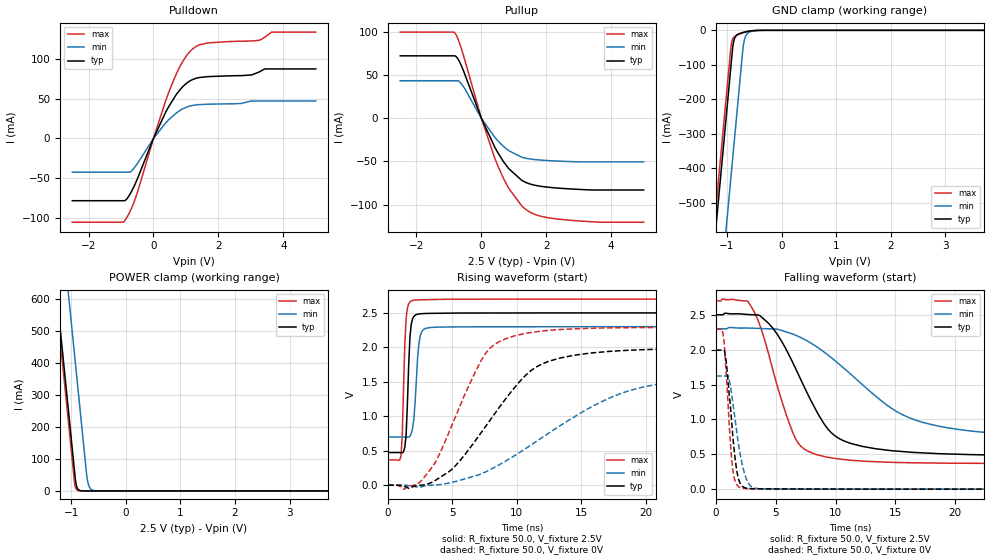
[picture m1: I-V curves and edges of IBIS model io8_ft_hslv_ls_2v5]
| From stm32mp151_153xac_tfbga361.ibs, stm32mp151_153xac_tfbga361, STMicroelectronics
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[Model]   io8_ft_hslv_ls_2v5
Model_type I/O
Polarity   Non-Inverting
Enable   Active-Low
| CAP_THRESHOLD on pad IOFT is "UDTCAPC" :
| Rising=20.00f vddiom   Falling=80.00f vddiom
| C_comp min and max val. don't necessarily correlate with the min and max pvt
| but are the smallest and greatest pad capacitance found.
| var   typ   min   max
C_comp   3.57714pF  3.54080pF  3.63503pF
|C_comp_pullup   2.11645pF  2.17895pF  2.03325pF
|C_comp_pulldown   1.46069pF  1.36185pF  1.60178pF
Vinl = 920.0mV
Vinh = 1.62V
Vmeas = 1.25V   | Reference voltage for timing measurements
Cref  = 50.0pF   | Timing specification test load capacitance value
Rref  = 100.0MOhm   | Timing specification test load resistance value
Vref  = 0V   | Timing specification test load voltage
[Model Spec]
| TIME_THRESHOLD on pin ZIV11 is "CMOS" :
| Rising=40.00f vdd   Falling=60.00f vdd
Vinl 1.03860V 964.60000mV 1.11860V
Vinh 1.36340V 1.26240V 1.44140V
| variable   typ   min   max
[Temperature Range] 25.0 140.0 -40.0
| variable   typ   min   max
[Voltage Range] 2.5V 2.3V 2.7V
| variable   typ   min   max
[POWER Clamp Reference] 2.5V 2.3V 2.7V
| variable   typ   min   max
[GND Clamp Reference] 0V 0V 0V
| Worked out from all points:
|   slope of the pulldown table from 0 to 0.375 V, typ, clamps not added: 11.3 ohm
|   slope of the pullup table from 0 to 0.375 V, typ, clamps not added: 12.3 ohm
|   GND clamp passes 1 mA (typ) near -0.52 V on its own axis
|   POWER clamp passes 1 mA (typ) near -0.83 V on its own axis
|   rising waveform, R_fixture 50.0, V_fixture 2.5V: 20-80 % time 252ps typ, 332ps min, 234ps max; typ from 0.473 V to 2.5 V
|   falling waveform, R_fixture 50.0, V_fixture 2.5V: 20-80 % time 3.71ns typ, 7.3ns min, 2.47ns max; typ from 2.5 V to 0.473 V
|   rising waveform, R_fixture 50.0, V_fixture 0V: 20-80 % time 4.92ns typ, 8.72ns min, 3.3ns max; typ from 0 V to 1.99 V
|   falling waveform, R_fixture 50.0, V_fixture 0V: 20-80 % time 643ps typ, 879ps min, 507ps max; typ from 1.99 V to 0 V
[POWER Clamp]
-2.5V     2.719A     3.084A     2.683A
-1.28V    644.8mA    1.01A      609.5mA
-1.26V    610.8mA    976.1mA    575.5mA
-1.04V    236.8mA    602.1mA    201.5mA
-940mV    66.83mA    432.1mA    31.5mA
-930mV    49.83mA    415.1mA    19.15mA
-910mV    22.88mA    381.1mA    7.077mA
-880mV    7.117mA    330.1mA    1.59mA
-710mV    9.523uA    43.89mA    337nA
-670mV    2.008uA    14.27mA    46.3nA
-600mV    132.9nA    1.998mA    1.599nA
5V        0A         0A         0A
[GND Clamp]
-2.5V     -2.779A    -3.101A    -2.723A
-1.26V    -670.8mA   -992.7mA   -614.5mA
-930mV    -109.8mA   -431.7mA   -53.54mA
-910mV    -75.83mA   -397.7mA   -32.67mA
-880mV    -35.28mA   -346.7mA   -21.39mA
-850mV    -20.07mA   -295.7mA   -16.99mA
-790mV    -10.9mA    -193.7mA   -12.02mA
-710mV    -6.374mA   -57.93mA   -7.219mA
-690mV    -5.545mA   -35.45mA   -6.225mA
-640mV    -3.775mA   -11.96mA   -4.068mA
-540mV    -1.354mA   -2.661mA   -1.223mA
5V        6.965nA    2.133uA    347.4pA
| variable   typ   min   max
[Pullup Reference] 2.5V 2.3V 2.7V
| variable   typ   min   max
[Pulldown Reference] 0V 0V 0V
[Pullup]
-2.5V     72.33mA    43.48mA    99.82mA
-800mV    72.04mA    43.48mA    97.99mA
-700mV    67.32mA    43.03mA    89.87mA
-570mV    56.71mA    37.64mA    75.05mA
0V        9.19pA     1.4nA      5.79pA
410mV     -33.26mA   -21.8mA    -45.97mA
840mV     -58.17mA   -37.44mA   -80.95mA
1.36V     -74.11mA   -46.17mA   -105.2mA
1.71V     -78mA      -48.02mA   -112.1mA
2.4V      -80.94mA   -49.62mA   -116.8mA
3.63V     -83.02mA   -50.48mA   -120.3mA
5V        -83.02mA   -50.48mA   -120.3mA
[Pulldown]
-2.5V     -78.63mA   -42.6mA    -105.8mA
-870mV    -78.28mA   -42.6mA    -102.9mA
-710mV    -69.32mA   -42.37mA   -91.24mA
-540mV    -55.23mA   -34.22mA   -73.64mA
0V        0A         -2pA       0A
470mV     40.29mA    23.69mA    58.27mA
850mV     63.07mA    36.18mA    93.59mA
1.21V     74.52mA    41.78mA    113.2mA
1.67V     78.14mA    43.3mA     120.7mA
3.22V     83.36mA    47.41mA    123.9mA
3.64V     87.89mA    47.41mA    134.4mA
5V        87.89mA    47.41mA    134.4mA
[Ramp]
dV/dt_r 1.19545V/4.91677ns 973.4037mV/8.72114ns 1.37489V/3.29665ns
dV/dt_f 1.21605V/3.70901ns 960.46445mV/7.30278ns 1.39953V/2.47124ns
R_load = 50.0
| Removed startup time: 0s 0s 0s  .
| Removed end time: 37.9ns.
[Rising Waveform]
R_fixture   = 50.0
V_fixture   = 2.5V
V_fixture_min = 2.3V
V_fixture_max = 2.7V
0s        473.2mV    699.2mV    367.5mV
1ns       471.2mV    699.3mV    422.8mV
1.1ns     468.9mV    699.3mV    706.3mV
1.3ns     550mV      699mV      2.037V
1.4ns     722.3mV    698.1mV    2.415V
1.7ns     2.151V     709.6mV    2.658V
1.9ns     2.412V     822.8mV    2.679V
2.4ns     2.484V     2.062V     2.689V
3ns       2.492V     2.279V     2.691V
37.9ns    2.5V       2.3V       2.7V
| Removed startup time: 0s 0s 0s  .
| Removed end time: 299.9ns.
[Falling Waveform]
R_fixture   = 50.0
V_fixture   = 2.5V
V_fixture_min = 2.3V
V_fixture_max = 2.7V
0s        2.5V       2.3V       2.7V
3ns       2.5V       2.308V     2.602V
4.8ns     2.298V     2.299V     1.68V
7ns       1.604V     2.183V     633.8mV
9.5ns     834.9mV    1.905V     452.8mV
12.5ns    605.2mV    1.46V      399.2mV
15.5ns    539.8mV    1.077V     380.9mV
19.2ns    505.7mV    884.9mV    372.7mV
37.4ns    474.8mV    719.7mV    367.5mV
299.9ns   473.2mV    699.2mV    367.4mV
| Removed startup time: 0s 0s 0s  .
| Removed end time: 299.9ns.
[Rising Waveform]
R_fixture   = 50.0
V_fixture   = 0V
V_fixture_min = 0V
V_fixture_max = 0V
0s        121.5nV    120.2nV    -3.624uV
2.1ns     -10.51mV   -20.62mV   5.073mV
3.4ns     41.57mV    46.01uV    255.4mV
7ns       702.1mV    147.2mV    1.724V
8.2ns     1.017V     250.7mV    2.031V
11.3ns    1.689V     607.8mV    2.22V
15.1ns    1.902V     1.063V     2.273V
21.6ns    1.975V     1.483V     2.289V
37.4ns    1.992V     1.612V     2.291V
299.9ns   1.992V     1.622V     2.291V
| Removed startup time: 0s 0s 0s  .
| Removed end time: 37.9ns.
[Falling Waveform]
R_fixture   = 50.0
V_fixture   = 0V
V_fixture_min = 0V
V_fixture_max = 0V
0s        1.992V     1.622V     2.291V
500ps     1.992V     1.622V     2.297V
800ps     1.906V     1.622V     1.798V
1.1ns     1.367V     1.581V     947.2mV
1.4ns     775.4mV    1.245V     283mV
1.7ns     307.8mV    864.7mV    75.37mV
2.1ns     60.82mV    432.1mV    17.99mV
2.7ns     9.659mV    88.46mV    7.38mV
3.6ns     4.647mV    6.815mV    5.727mV
37.9ns    6.876uV    62.89uV    15.16uV
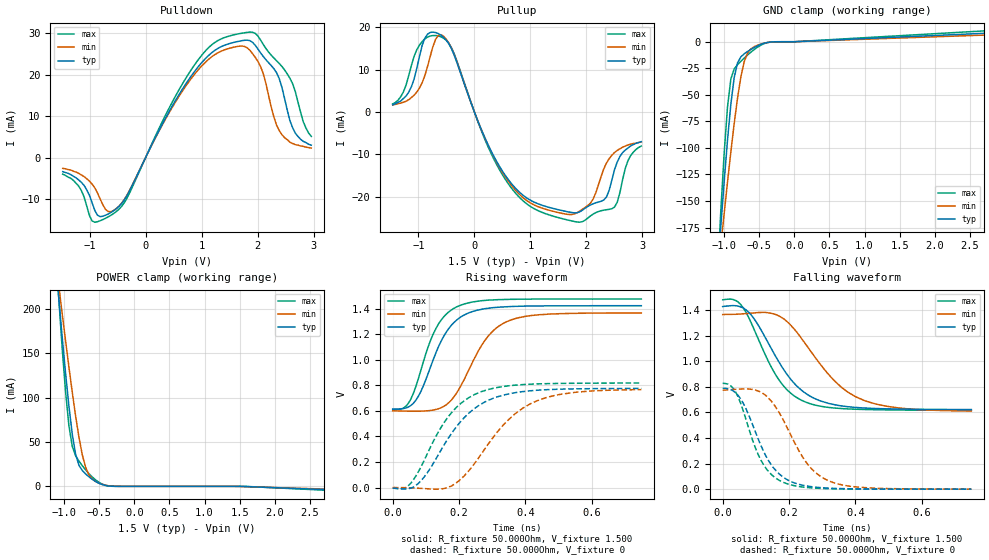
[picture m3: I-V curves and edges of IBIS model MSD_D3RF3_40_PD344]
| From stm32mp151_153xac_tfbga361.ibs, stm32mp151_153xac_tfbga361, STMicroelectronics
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[Model] MSD_D3RF3_40_PD344
Model_type   I/O
C_comp 2.325pF   2.244pF   2.446pF
Vinh = 925.000mV
Vinl = 575.000mV
Vmeas = 750.000mV
Vref = 750.000mV
[Model Spec]
Vinh   925.000mV   888.000mV   963.000mV
Vinl   575.000mV   538.000mV   613.000mV
Vmeas   750.000mV   713.000mV   788.000mV
Vref   750.000mV   713.000mV   788.000mV
[Temperature Range]   25.000   125.000   -40.000
[Voltage Range]   1.500V   1.425V   1.575V
[GND Clamp Reference]   0.00V   0.00V   0.00V
[Pulldown Reference]   0.00V   0.00V   0.00V
[POWER Clamp Reference]   1.500V   1.425V   1.575V
[Pullup Reference]   1.500V   1.425V   1.575V
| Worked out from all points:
|   slope of the pulldown table from 0 to 0.225 V, typ, clamps not added: 36.6 ohm
|   slope of the pullup table from 0 to 0.225 V, typ, clamps not added: 31.2 ohm
|   GND clamp passes 1 mA (typ) near -0.40 V on its own axis
|   POWER clamp passes 1 mA (typ) near -0.41 V on its own axis
|   rising waveform, R_fixture 50.000Ohm, V_fixture 1.500: 20-80 % time 85.1ps typ, 102ps min, 74.9ps max; typ from 0.614 V to 1.42 V
|   rising waveform, R_fixture 50.000Ohm, V_fixture 0: 20-80 % time 134ps typ, 151ps min, 118ps max; typ from -0.004 V to 0.776 V
|   falling waveform, R_fixture 50.000Ohm, V_fixture 1.500: 20-80 % time 122ps typ, 148ps min, 105ps max; typ from 1.43 V to 0.622 V
|   falling waveform, R_fixture 50.000Ohm, V_fixture 0: 20-80 % time 86.4ps typ, 104ps min, 74.4ps max; typ from 0.789 V to 0 V
[GND Clamp]
-1.48V    -593.9mA   -479.7mA   -763.2mA
-1.098V   -218.2mA   -223.4mA   -220.2mA
-1.05V    -174.1mA   -192.4mA   -159.6mA
-1.002V   -131.9mA   -161.9mA   -105.2mA
-954.6mV  -92.83mA   -132.3mA   -61.52mA
-906.8mV  -59.01mA   -103.9mA   -35.14mA
-859.1mV  -33.8mA    -77.16mA   -25.62mA
-811.4mV  -19.9mA    -53.08mA   -21.6mA
-715.9mV  -11.4mA    -18.73mA   -15.4mA
-572.7mV  -5.412mA   -4.636mA   -7.313mA
-334.1mV  -240.8uA   -308.8uA   -242.5uA
2.959V    8.682mA    6.832mA    11.15mA
[Power Clamp]
-1.459V   577.4mA    478.9mA    722.8mA
-1.077V   210.9mA    225.3mA    210.2mA
-1.03V    168.1mA    194.5mA    155.5mA
-981.8mV  127.5mA    164.2mA    106.7mA
-934.1mV  90.43mA    134.6mA    68.21mA
-886.4mV  58.96mA    106.1mA    45.13mA
-838.6mV  36.12mA    79.33mA    34.57mA
-743.2mV  17.82mA    35.48mA    23.27mA
-647.7mV  10.71mA    12.79mA    14.31mA
-552.3mV  5.453mA    5.392mA    7.2mA
-313.6mV  90.62uA    219.4uA    108.4uA
2.98V     -4.416mA   -3.704mA   -5.362mA
[Pulldown]
-1.48V    -3.4mA     -2.6mA     -4mA
-1.193V   -5.4mA     -3.8mA     -6.9mA
-954.6mV  -10.92mA   -6.4mA     -15.27mA
-811.4mV  -14.22mA   -9.94mA    -15.22mA
-525mV    -12.36mA   -12.3mA    -13.02mA
906.8mV   21.31mA    20.61mA    22.96mA
1.289V    26.28mA    25.22mA    28.17mA
1.766V    28.25mA    26.78mA    30.06mA
2.052V    25.24mA    21.96mA    28.33mA
2.434V    16.92mA    5.5mA      21.96mA
2.673V    5.9mA      3.1mA      15.9mA
2.959V    3mA        2.3mA      5.1mA
[Pullup]
-1.459V   1.7mA      1.657mA    1.929mA
-1.173V   4.7mA      2.929mA    8.628mA
-838.6mV  18.38mA    10.7mA     17.71mA
-695.5mV  18.8mA     17.13mA    18.09mA
-552.3mV  17.7mA     17.94mA    17.47mA
640.9mV   -16.58mA   -16.97mA   -17.61mA
1.834V    -23.79mA   -23.77mA   -25.99mA
2.12V     -21.67mA   -20.55mA   -24.11mA
2.311V    -20.78mA   -13.39mA   -23.18mA
2.502V    -13.6mA    -9.557mA   -22.45mA
2.741V    -8.5mA     -7.786mA   -11.5mA
2.98V     -7mA       -7.043mA   -8.029mA
[Ramp]
R_load=50.000Ohm
dV/dt_r   473.460mV/109.500ps  459.269mV/127.500ps  503.190mV/97.000ps
dV/dt_f   473.460mV/104.500ps  459.269mV/128.000ps  503.190mV/90.000ps
[Rising waveform]
R_fixture=50.000Ohm
V_fixture=1.500
V_fixture_min=1.425
V_fixture_max=1.575
0s        614.5mV    600.9mV    611.3mV
39ps      622.5mV    598.7mV    634.6mV
69ps      680.8mV    597.9mV    785.5mV
108ps     901.6mV    602mV      1.11V
131ps     1.06V      612mV      1.248V
192ps     1.309V     737.8mV    1.413V
276ps     1.399V     1.145V     1.464V
345ps     1.415V     1.3V       1.472V
467ps     1.422V     1.357V     1.475V
749ps     1.423V     1.366V     1.475V
[Rising waveform]
R_fixture=50.000Ohm
V_fixture=0
0s        -3.738mV   807.5uV    -3.72mV
39ps      -10.46mV   -683uV     194.6uV
77ps      32.35mV    -4.576mV   122.6mV
169ps     392.7mV    4.086mV    559.9mV
207ps     523.1mV    70.71mV    662.6mV
253ps     631mV      211.8mV    735.6mV
345ps     730.7mV    521.5mV    795.1mV
437ps     762.2mV    681.6mV    811.3mV
552ps     772.7mV    746.3mV    816.4mV
749ps     776mV      766.7mV    818.4mV
[Falling waveform]
R_fixture=50.000Ohm
V_fixture=1.500
V_fixture_min=1.425
V_fixture_max=1.575
0s        1.427V     1.365V     1.48V
46ps      1.431V     1.368V     1.464V
77ps      1.386V     1.374V     1.349V
138ps     1.139V     1.378V     996.9mV
169ps     996mV      1.354V     855.9mV
245ps     758.2mV    1.151V     686mV
337ps     660.4mV    846.2mV    634.2mV
429ps     634.1mV    690.3mV    622.7mV
552ps     625.5mV    629.3mV    618.2mV
749ps     622.2mV    610.6mV    617.1mV
[Falling waveform]
R_fixture=50.000Ohm
V_fixture=0
0s        788.6mV    774mV      827mV
39ps      753.4mV    780.5mV    759.5mV
69ps      634.8mV    783.6mV    554.3mV
115ps     341.9mV    757.9mV    227.4mV
146ps     191.2mV    689.6mV    116.1mV
184ps     90.9mV     534.2mV    51.97mV
253ps     24.96mV    205mV      13.15mV
322ps     7.88mV     61.99mV    3.518mV
444ps     1.173mV    9.74mV     459.8uV
749ps     25.69uV    248.7uV    20.75uV
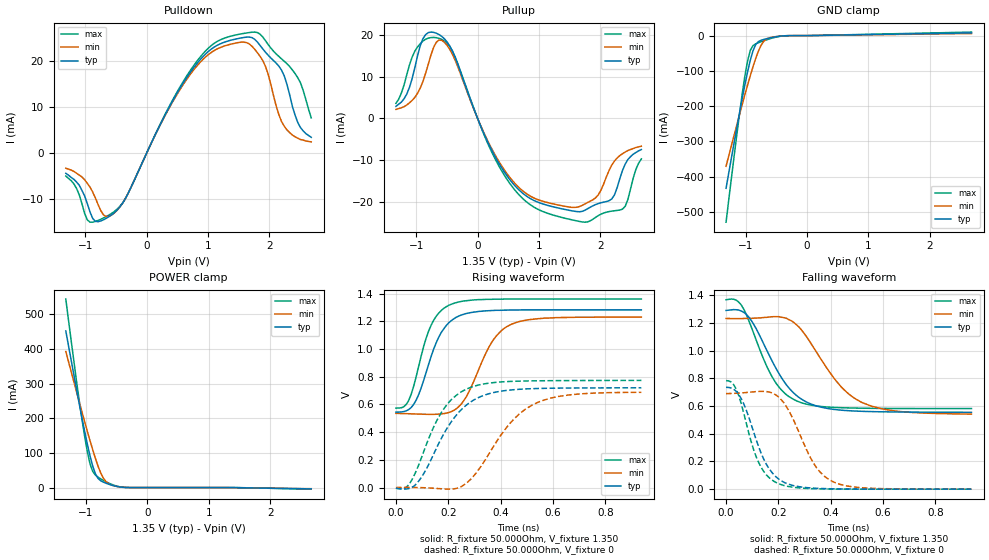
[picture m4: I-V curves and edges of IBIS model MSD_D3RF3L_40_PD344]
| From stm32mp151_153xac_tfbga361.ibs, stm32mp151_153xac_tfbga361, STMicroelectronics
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[Model] MSD_D3RF3L_40_PD344
Model_type   I/O
C_comp 2.333pF   2.249pF   2.455pF
Vinh = 810.000mV
Vinl = 540.000mV
Vmeas = 675.000mV
Vref = 675.000mV
[Model Spec]
Vinh   810.000mV   777.000mV   860.000mV
Vinl   540.000mV   507.000mV   590.000mV
Vmeas   675.000mV   642.000mV   725.000mV
Vref   675.000mV   642.000mV   725.000mV
[Temperature Range]   25.000   125.000   -40.000
[Voltage Range]   1.350V   1.283V   1.450V
[GND Clamp Reference]   0.00V   0.00V   0.00V
[Pulldown Reference]   0.00V   0.00V   0.00V
[POWER Clamp Reference]   1.350V   1.283V   1.450V
[Pullup Reference]   1.350V   1.283V   1.450V
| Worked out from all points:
|   slope of the pulldown table from 0 to 0.203 V, typ, clamps not added: 35.7 ohm
|   slope of the pullup table from 0 to 0.203 V, typ, clamps not added: 29.7 ohm
|   GND clamp passes 1 mA (typ) near -0.41 V on its own axis
|   POWER clamp passes 1 mA (typ) near -0.41 V on its own axis
|   rising waveform, R_fixture 50.000Ohm, V_fixture 1.350: 20-80 % time 87.9ps typ, 108ps min, 75.3ps max; typ from 0.545 V to 1.28 V
|   rising waveform, R_fixture 50.000Ohm, V_fixture 0: 20-80 % time 139ps typ, 165ps min, 119ps max; typ from -0.005 V to 0.72 V
|   falling waveform, R_fixture 50.000Ohm, V_fixture 1.350: 20-80 % time 135ps typ, 164ps min, 113ps max; typ from 1.29 V to 0.554 V
|   falling waveform, R_fixture 50.000Ohm, V_fixture 0: 20-80 % time 91.3ps typ, 109ps min, 78ps max; typ from 0.735 V to 0 V
[GND Clamp]
-1.318V   -432.8mA   -370.3mA   -528.8mA
-1.142V   -260.6mA   -252.7mA   -280.2mA
-1.055V   -178.2mA   -195.3mA   -165.2mA
-1.011V   -139.1mA   -167.2mA   -114.1mA
-966.7mV  -102.3mA   -139.7mA   -71.26mA
-922.7mV  -69.52mA   -113.2mA   -41.65mA
-878.8mV  -42.92mA   -87.94mA   -28.29mA
-834.9mV  -25.34mA   -64.54mA   -23.37mA
-790.9mV  -16.86mA   -43.9mA    -20.2mA
-703mV    -10.78mA   -15.99mA   -14.6mA
-527.3mV  -3.885mA   -3.295mA   -5.182mA
2.68V     7.735mA    6.026mA    10.03mA
[Power Clamp]
-1.33V    451.9mA    392.5mA    543.7mA
-1.111V   241.7mA    247mA      250.6mA
-1.023V   162.1mA    190.1mA    147.8mA
-978.8mV  125mA      162.2mA    103.3mA
-934.9mV  90.96mA    135mA      67.89mA
-890.9mV  61.61mA    108.7mA    46.32mA
-847mV    39.32mA    83.78mA    35.87mA
-803mV    26.01mA    60.99mA    29.83mA
-715.1mV  15.42mA    26.29mA    20.43mA
-671.2mV  12.23mA    16.24mA    16.32mA
-407.6mV  863.9uA    1.131mA    1.056mA
2.668V    -3.889mA   -3.241mA   -4.623mA
[Pulldown]
-1.318V   -4.4mA     -3.3mA     -5mA
-922.7mV  -12.81mA   -7.4mA     -14.99mA
-703mV    -14.46mA   -13.41mA   -14.07mA
-571.2mV  -13.38mA   -13.45mA   -13.07mA
-351.5mV  -9.984mA   -9.963mA   -9.952mA
747mV     18.14mA    17.69mA    18.59mA
1.582V    25.02mA    24.01mA    25.9mA
1.889V    22.57mA    20.05mA    25.16mA
2.153V    18.81mA    8.3mA      20.91mA
2.329V    12.6mA     4.4mA      18.73mA
2.461V    6.6mA      3.2mA      16.3mA
2.68V     3.4mA      2.4mA      7.6mA
[Pullup]
-1.33V    2.9mA      2.152mA    3.607mA
-1.155V   5.8mA      3.21mA     10.41mA
-978.8mV  15mA       6.03mA     17.15mA
-715.1mV  20.68mA    17.11mA    19.47mA
-451.5mV  17.38mA    16.55mA    17.25mA
251.5mV   -8.249mA   -7.87mA    -8.718mA
866.7mV   -19.34mA   -18.75mA   -20.85mA
1.702V    -22.36mA   -20.93mA   -24.89mA
1.965V    -20.5mA    -18.41mA   -23.39mA
2.185V    -19.39mA   -11.27mA   -22.3mA
2.361V    -12.5mA    -8.49mA    -21.82mA
2.668V    -7.5mA     -6.695mA   -9.748mA
[Ramp]
R_load=50.000Ohm
dV/dt_r   435.000mV/113.500ps  414.899mV/138.000ps  466.080mV/98.000ps
dV/dt_f   435.000mV/113.500ps  414.899mV/138.000ps  466.080mV/95.500ps
[Rising waveform]
R_fixture=50.000Ohm
V_fixture=1.350
V_fixture_min=1.283
V_fixture_max=1.450
0s        544.9mV    535.7mV    574.2mV
39ps      553.7mV    533.6mV    599.2mV
68ps      600.9mV    531.8mV    732.9mV
106ps     773.8mV    529.5mV    1.019V
135ps     949.6mV    528.7mV    1.174V
202ps     1.19V      541.9mV    1.316V
269ps     1.257V     655.5mV    1.349V
374ps     1.279V     1.071V     1.36V
441ps     1.282V     1.179V     1.361V
938ps     1.283V     1.231V     1.361V
[Rising waveform]
R_fixture=50.000Ohm
V_fixture=0
0s        -5.083mV   834.7uV    -4.644mV
48ps      -8.167mV   853.5uV    17.86mV
87ps      46.58mV    -64.2uV    163.2mV
173ps     353.1mV    -8.726mV   539.5mV
221ps     499.5mV    -9.33mV    649.9mV
278ps     608.5mV    46.25mV    717.8mV
432ps     703.3mV    454.4mV    765.9mV
527ps     714.4mV    602mV      770.5mV
662ps     718.7mV    668.8mV    772.5mV
938ps     720.4mV    687.9mV    773.6mV
[Falling waveform]
R_fixture=50.000Ohm
V_fixture=1.350
V_fixture_min=1.283
V_fixture_max=1.450
0s        1.289V     1.231V     1.366V
48ps      1.292V     1.23V      1.35V
87ps      1.241V     1.231V     1.216V
144ps     1.047V     1.238V     936.1mV
183ps     898.7mV    1.244V     788.1mV
269ps     676.1mV    1.186V     637.3mV
422ps     573.2mV    777.9mV    588.9mV
518ps     561.5mV    626.4mV    584.1mV
662ps     556.5mV    560.8mV    581.8mV
938ps     554.4mV    541.4mV    581.3mV
[Falling waveform]
R_fixture=50.000Ohm
V_fixture=0
0s        734.7mV    689.4mV    782.8mV
39ps      705.5mV    691.8mV    721.5mV
68ps      614mV      695.5mV    546mV
125ps     303.6mV    704.7mV    191.1mV
163ps     151.8mV    701.3mV    85.68mV
202ps     71.84mV    663.2mV    38.85mV
240ps     35.16mV    566.3mV    18.64mV
336ps     7.3mV      182.7mV    3.156mV
413ps     2.343mV    49.99mV    768.9uV
938ps     5.739uV    100.4uV    4.018uV
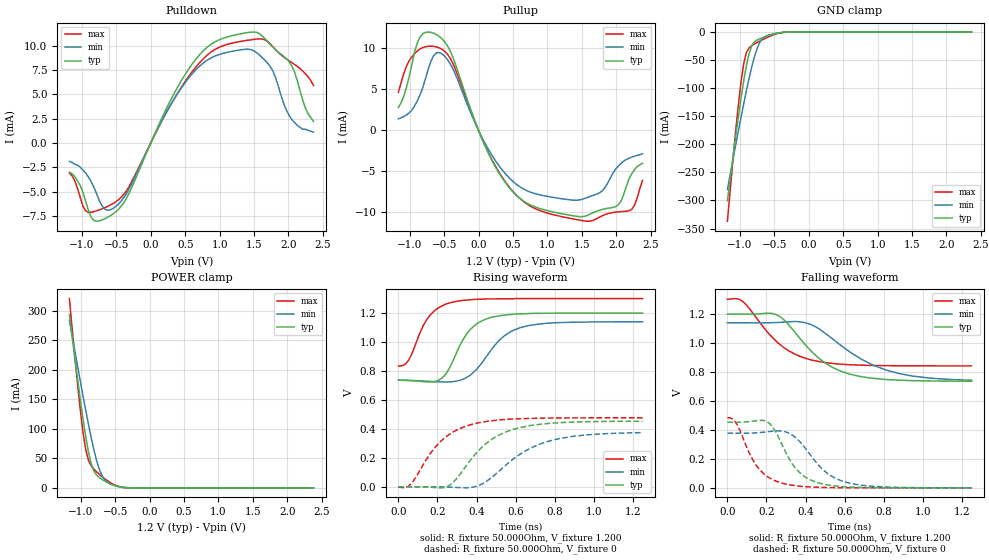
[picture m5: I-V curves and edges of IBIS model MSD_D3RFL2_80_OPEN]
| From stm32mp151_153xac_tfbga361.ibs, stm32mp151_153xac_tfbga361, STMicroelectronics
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[Model] MSD_D3RFL2_80_OPEN
Model_type   I/O
C_comp 2.581pF   2.493pF   2.708pF
Vinh = 820.000mV
Vinl = 380.000mV
Vmeas = 600.000mV
Vref = 600.000mV
[Model Spec]
Vinh   820.000mV   790.000mV   870.000mV
Vinl   380.000mV   350.000mV   430.000mV
Vmeas   600.000mV   570.000mV   650.000mV
Vref   600.000mV   570.000mV   650.000mV
[Temperature Range]   25.000   125.000   -40.000
[Voltage Range]   1.200V   1.140V   1.300V
[GND Clamp Reference]   0.00V   0.00V   0.00V
[Pulldown Reference]   0.00V   0.00V   0.00V
[POWER Clamp Reference]   1.200V   1.140V   1.300V
[Pullup Reference]   1.200V   1.140V   1.300V
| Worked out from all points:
|   slope of the pulldown table from 0 to 0.18 V, typ, clamps not added: 63.6 ohm
|   slope of the pullup table from 0 to 0.18 V, typ, clamps not added: 52.8 ohm
|   GND clamp passes 1 mA (typ) near -0.40 V on its own axis
|   POWER clamp passes 1 mA (typ) near -0.41 V on its own axis
|   rising waveform, R_fixture 50.000Ohm, V_fixture 1.200: 20-80 % time 120ps typ, 157ps min, 106ps max; typ from 0.736 V to 1.2 V
|   rising waveform, R_fixture 50.000Ohm, V_fixture 0: 20-80 % time 204ps typ, 247ps min, 181ps max; typ from 0 V to 0.453 V
|   falling waveform, R_fixture 50.000Ohm, V_fixture 1.200: 20-80 % time 217ps typ, 288ps min, 202ps max; typ from 1.2 V to 0.737 V
|   falling waveform, R_fixture 50.000Ohm, V_fixture 0: 20-80 % time 125ps typ, 159ps min, 120ps max; typ from 0.453 V to 0 V
[GND Clamp]
-1.182V   -300.5mA   -280.4mA   -337mA
-1.064V   -188.1mA   -202.5mA   -178.5mA
-984.9mV  -118.6mA   -152.2mA   -89.49mA
-945.5mV  -87.16mA   -127.9mA   -56.6mA
-906.1mV  -59.71mA   -104.4mA   -36.4mA
-866.7mV  -38.14mA   -82.14mA   -27.92mA
-827.3mV  -24.29mA   -61.54mA   -24.05mA
-748.5mV  -14mA      -28.45mA   -18.47mA
-709.1mV  -11.76mA   -17.8mA    -15.89mA
-630.3mV  -8.132mA   -7.75mA    -11.05mA
-472.7mV  -2.557mA   -2.242mA   -3.323mA
2.364V    29.58nA    484.6nA    2.864nA
[Power Clamp]
-1.164V   293.6mA    283.6mA    320.6mA
-1.085V   219.6mA    231.9mA    221.3mA
-1.006V   149.3mA    180.9mA    132.2mA
-966.7mV  116.7mA    156mA      94.33mA
-927.3mV  86.87mA    131.6mA    64.9mA
-887.9mV  61.07mA    108mA      46.71mA
-809.1mV  28.38mA    64.84mA    31.83mA
-730.3mV  17.49mA    31.58mA    22.97mA
-651.5mV  11.58mA    13.7mA     15.38mA
-533.3mV  4.956mA    4.897mA    6.46mA
-336.4mV  215.7uA    403.7uA    242.8uA
2.382V    -24.83nA   -515.5nA   -2.721nA
[Pulldown]
-1.182V   -3mA       -1.9mA     -3.1mA
-945.5mV  -6.01mA    -3.1mA     -7mA
-827.3mV  -7.98mA    -4.55mA    -7.07mA
-669.7mV  -7.799mA   -6.81mA    -6.67mA
-512.1mV  -7.115mA   -6.556mA   -6.075mA
-315.1mV  -5.181mA   -4.738mA   -4.478mA
590.9mV   8.002mA    7.016mA    7.22mA
906.1mV   10.28mA    8.84mA     9.488mA
1.3V      11.21mA    9.56mA     10.43mA
1.733V    10.11mA    7.871mA    10.19mA
2.009V    8.35mA     2.83mA     8.43mA
2.364V    2.2mA      1.1mA      5.9mA
[Pullup]
-1.164V   2.8mA      1.405mA    4.654mA
-1.045V   5.3mA      1.905mA    7.869mA
-887.9mV  10.72mA    3.629mA    9.704mA
-690.9mV  11.96mA    8.455mA    10.28mA
-454.5mV  10.36mA    8.679mA    9.333mA
175.8mV   -3.334mA   -2.766mA   -3.264mA
687.9mV   -8.798mA   -7.289mA   -8.88mA
1.476V    -10.51mA   -8.453mA   -10.95mA
1.791V    -9.644mA   -7.404mA   -10.42mA
1.988V    -9.3mA     -4.749mA   -9.962mA
2.224V    -5.3mA     -3.248mA   -9.621mA
2.382V    -4mA       -2.848mA   -6.085mA
[Ramp]
R_load=50.000Ohm
dV/dt_r   275.100mV/163.000ps  234.149mV/205.500ps  280.380mV/144.000ps
dV/dt_f   275.100mV/172.000ps  234.151mV/228.000ps  280.380mV/161.500ps
[Rising waveform]
R_fixture=50.000Ohm
V_fixture=1.200
V_fixture_min=1.140
V_fixture_max=1.300
0s        736.4mV    736.7mV    834.5mV
52ps      734.3mV    735.2mV    873.9mV
154ps     724.7mV    728.8mV    1.172V
218ps     746mV      724.6mV    1.246V
269ps     841.1mV    725.3mV    1.273V
371ps     1.091V     774mV      1.292V
486ps     1.174V     964.6mV    1.298V
575ps     1.19V      1.071V     1.299V
690ps     1.198V     1.119V     1.3V
1.25ns    1.2V       1.14V      1.3V
[Rising waveform]
R_fixture=50.000Ohm
V_fixture=0
0s        105.3uV    109uV      -2.402mV
64ps      546.8uV    381.7uV    19.7mV
166ps     -2.704mV   467.8uV    234.8mV
243ps     -1.928mV   -1.373mV   344.5mV
294ps     50.27mV    -4.322mV   388.9mV
358ps     165.6mV    -6.067mV   424.4mV
473ps     323.5mV    59.86mV    455.7mV
613ps     406.3mV    216.6mV    470.1mV
830ps     443.5mV    334.8mV    475.5mV
1.25ns    452.8mV    374.4mV    476.9mV
[Falling waveform]
R_fixture=50.000Ohm
V_fixture=1.200
V_fixture_min=1.140
V_fixture_max=1.300
0s        1.2V       1.14V      1.302V
77ps      1.2V       1.14V      1.289V
243ps     1.2V       1.141V     1.022V
294ps     1.155V     1.145V     964.4mV
409ps     973mV      1.136V     890.9mV
498ps     865.4mV    1.07V      865.9mV
575ps     809.1mV    990.1mV    854.8mV
805ps     749.3mV    817.3mV    844mV
971ps     739.7mV    768.2mV    842.7mV
1.25ns    736.6mV    742.9mV    842.2mV
[Falling waveform]
R_fixture=50.000Ohm
V_fixture=0
0s        453mV      377.1mV    484.7mV
39ps      452.7mV    376.9mV    459.1mV
128ps     460mV      378.4mV    198.4mV
192ps     463mV      385.3mV    90.48mV
281ps     295.2mV    391.2mV    31.83mV
332ps     166.1mV    364.5mV    17.78mV
396ps     76.76mV    278.9mV    8.491mV
498ps     23.85mV    114.9mV    2.685mV
613ps     6.508mV    36.69mV    635.9uV
1.25ns    -3.874uV   69.58uV    13.07uV
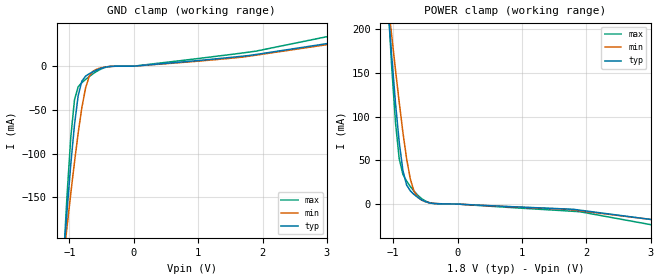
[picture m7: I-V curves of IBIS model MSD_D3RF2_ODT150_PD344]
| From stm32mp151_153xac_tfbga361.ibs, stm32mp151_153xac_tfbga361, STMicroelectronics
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[Model] MSD_D3RF2_ODT150_PD344
Model_type   Input
C_comp 2.269pF   2.203pF   2.333pF
Vinh = 1.150V
Vinl = 650.000mV
[Model Spec]
Vinh   1.150V   1.100V   1.200V
Vinl   650.000mV   600.000mV   700.000mV
[Temperature Range]   25.000   125.000   -40.000
[Voltage Range]   1.800V   1.700V   1.900V
[GND Clamp Reference]   0.00V   0.00V   0.00V
[POWER Clamp Reference]   1.800V   1.700V   1.900V
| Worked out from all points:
|   GND clamp passes 1 mA (typ) near -0.43 V on its own axis
|   POWER clamp passes 1 mA (typ) near -0.41 V on its own axis
[GND Clamp]
-1.785V   -947.5mA   -705.4mA   -1.31A
-1.094V   -220.5mA   -221.6mA   -225mA
-1.036V   -164.6mA   -183.2mA   -146.9mA
-978.8mV  -112.5mA   -145.7mA   -81.62mA
-921.2mV  -67.08mA   -109.8mA   -38.49mA
-863.6mV  -33.67mA   -76.44mA   -23.51mA
-806.1mV  -16.96mA   -47.21mA   -18.78mA
-748.5mV  -11.4mA    -24.73mA   -15.17mA
-633.3mV  -6.345mA   -5.743mA   -8.707mA
-403mV    -598.4uA   -545.8uA   -668.4uA
1.9V      13.4mA     12.62mA    17.22mA
3.57V     32.2mA     30.79mA    42.28mA
[Power Clamp]
-1.77V    958.6mA    722mA      1.314A
-1.079V   224.2mA    231mA      229mA
-1.021V   167.7mA    191.9mA    155.2mA
-963.6mV  115.6mA    153.5mA    93.26mA
-906.1mV  70.96mA    116.5mA    51.77mA
-848.5mV  38.31mA    82mA       34.04mA
-790.9mV  21.76mA    51.8mA     26.22mA
-733.3mV  15.11mA    28.66mA    20.1mA
-675.8mV  10.98mA    14.62mA    14.76mA
-560.6mV  4.926mA    4.678mA    6.418mA
1.915V    -7.093mA   -7.852mA   -8.945mA
3.585V    -23.21mA   -22.8mA    -31.36mA
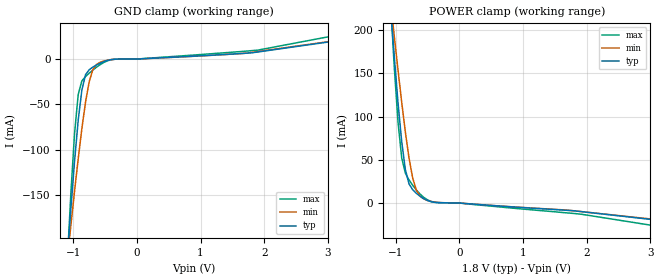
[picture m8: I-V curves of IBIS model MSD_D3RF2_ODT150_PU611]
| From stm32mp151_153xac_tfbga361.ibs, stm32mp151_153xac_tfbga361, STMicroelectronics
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[Model] MSD_D3RF2_ODT150_PU611
Model_type   Input
C_comp 2.376pF   2.308pF   2.443pF
Vinh = 1.150V
Vinl = 650.000mV
[Temperature Range]   25.000   125.000   -40.000
[Voltage Range]   1.800V   1.700V   1.900V
[GND Clamp Reference]   0.00V   0.00V   0.00V
[POWER Clamp Reference]   1.800V   1.700V   1.900V
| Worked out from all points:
|   GND clamp passes 1 mA (typ) near -0.43 V on its own axis
|   POWER clamp passes 1 mA (typ) near -0.40 V on its own axis
[GND Clamp]
-1.785V   -949mA     -706.6mA   -1.312A
-1.094V   -221.2mA   -222.2mA   -225.9mA
-1.036V   -165.2mA   -183.7mA   -147.9mA
-978.8mV  -113mA     -146.2mA   -82.42mA
-921.2mV  -67.6mA    -110.2mA   -39.19mA
-863.6mV  -34.14mA   -76.81mA   -24.13mA
-806.1mV  -17.37mA   -47.52mA   -19.32mA
-748.5mV  -11.76mA   -25mA      -15.63mA
-690.9mV  -8.9mA     -11.64mA   -12.2mA
-575.8mV  -4.552mA   -3.541mA   -6.17mA
1.9V      7.819mA    8.308mA    9.858mA
3.57V     24.45mA    24.81mA    32.08mA
[Power Clamp]
-1.77V    960.3mA    723.5mA    1.316A
-1.079V   224.9mA    231.7mA    230mA
-1.021V   168.5mA    192.5mA    156.1mA
-963.6mV  116.3mA    154.1mA    94.05mA
-906.1mV  71.51mA    117mA      52.48mA
-848.5mV  38.81mA    82.45mA    34.66mA
-790.9mV  22.19mA    52.2mA     26.76mA
-733.3mV  15.47mA    29mA       20.55mA
-675.8mV  11.28mA    14.9mA     15.13mA
-560.6mV  5.104mA    4.855mA    6.638mA
-387.9mV  794.2uA    1.018mA    892.6uA
3.585V    -23.75mA   -23.04mA   -32.4mA
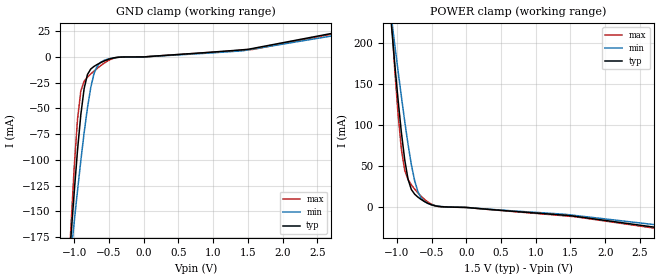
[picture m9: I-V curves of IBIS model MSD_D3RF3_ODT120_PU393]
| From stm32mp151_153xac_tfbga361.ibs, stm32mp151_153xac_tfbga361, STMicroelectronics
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[Model] MSD_D3RF3_ODT120_PU393
Model_type   Input
C_comp 2.300pF   2.255pF   2.402pF
Vinh = 925.000mV
Vinl = 575.000mV
[Temperature Range]   25.000   125.000   -40.000
[Voltage Range]   1.500V   1.425V   1.575V
[GND Clamp Reference]   0.00V   0.00V   0.00V
[POWER Clamp Reference]   1.500V   1.425V   1.575V
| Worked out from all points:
|   GND clamp passes 1 mA (typ) near -0.44 V on its own axis
|   POWER clamp passes 1 mA (typ) near -0.37 V on its own axis
[GND Clamp]
-1.48V    -618.6mA   -487.8mA   -825.6mA
-1.05V    -175.7mA   -191.6mA   -166.2mA
-1.002V   -131.4mA   -160.4mA   -107.3mA
-954.6mV  -90.85mA   -129.9mA   -60.79mA
-906.8mV  -56.21mA   -100.8mA   -33.22mA
-859.1mV  -30.8mA    -73.67mA   -23.63mA
-763.6mV  -11.74mA   -29.73mA   -16.63mA
-715.9mV  -9.163mA   -16.02mA   -13.73mA
-620.5mV  -5.533mA   -5.124mA   -8.443mA
-334.1mV  -171.4uA   -252.4uA   -157uA
1.48V     7.249mA    6.571mA    6.811mA
2.959V    26.04mA    23.19mA    25.43mA
[Power Clamp]
-1.459V   620.8mA    498mA      819mA
-1.077V   220.9mA    230mA      229.7mA
-1.03V    174.3mA    197.5mA    167.5mA
-981.8mV  130.3mA    165.6mA    112.8mA
-934.1mV  90.79mA    134.5mA    70.26mA
-886.4mV  57.81mA    104.6mA    45.13mA
-838.6mV  34.21mA    76.7mA     33.91mA
-743.2mV  16.06mA    32.33mA    22.25mA
-695.5mV  12.46mA    18.77mA    17.52mA
-600mV    7.018mA    7.089mA    9.628mA
-361.4mV  914.9uA    1.096mA    753.2uA
2.98V     -27.09mA   -23.52mA   -28.45mA
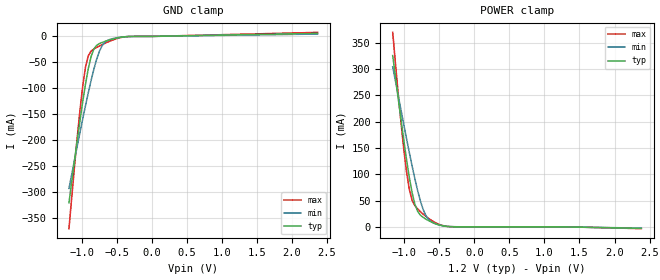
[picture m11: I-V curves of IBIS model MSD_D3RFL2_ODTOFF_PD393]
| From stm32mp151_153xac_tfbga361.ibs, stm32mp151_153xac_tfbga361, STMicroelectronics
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[Model] MSD_D3RFL2_ODTOFF_PD393
Model_type   Input
C_comp 2.371pF   2.286pF   2.495pF
Vinh = 820.000mV
Vinl = 380.000mV
[Temperature Range]   25.000   125.000   -40.000
[Voltage Range]   1.200V   1.140V   1.300V
[GND Clamp Reference]   0.00V   0.00V   0.00V
[POWER Clamp Reference]   1.200V   1.140V   1.300V
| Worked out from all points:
|   GND clamp passes 1 mA (typ) near -0.40 V on its own axis
|   POWER clamp passes 1 mA (typ) near -0.41 V on its own axis
[GND Clamp]
-1.182V   -319.9mA   -292.3mA   -369.8mA
-1.064V   -199.6mA   -210.9mA   -193.8mA
-984.9mV  -125mA     -158.3mA   -94.71mA
-945.5mV  -91.25mA   -132.8mA   -58.69mA
-906.1mV  -61.84mA   -108.3mA   -37.14mA
-866.7mV  -38.93mA   -84.96mA   -28.3mA
-827.3mV  -24.42mA   -63.39mA   -24.32mA
-787.9mV  -17.3mA    -44.36mA   -21.34mA
-709.1mV  -11.6mA    -17.85mA   -15.93mA
-551.5mV  -4.866mA   -4.098mA   -6.614mA
-315.1mV  -156.8uA   -223.4uA   -144.5uA
2.364V    5.864mA    4.498mA    7.703mA
[Power Clamp]
-1.164V   326mA      304.6mA    370.2mA
-1.085V   243.7mA    249.3mA    252.2mA
-1.006V   164.7mA    194.7mA    147.7mA
-966.7mV  127.9mA    167.9mA    104.4mA
-927.3mV  94.25mA    141.6mA    71.18mA
-887.9mV  65.36mA    116.1mA    50.8mA
-809.1mV  29.55mA    69.29mA    34.06mA
-730.3mV  17.88mA    33.16mA    24.15mA
-690.9mV  14.54mA    21.4mA     19.82mA
-572.7mV  6.775mA    6.639mA    9.117mA
-336.4mV  171.6uA    330.2uA    199.5uA
2.382V    -3.02mA    -2.487mA   -3.59mA
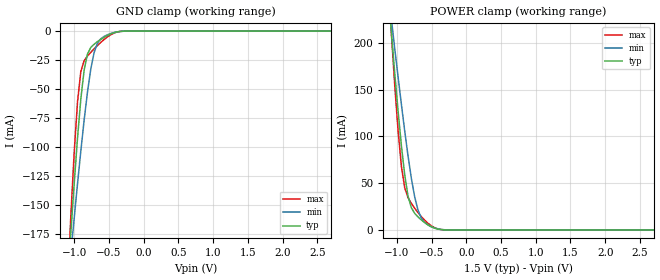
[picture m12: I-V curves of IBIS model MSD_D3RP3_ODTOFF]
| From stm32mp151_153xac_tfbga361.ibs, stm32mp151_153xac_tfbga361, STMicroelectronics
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[Model] MSD_D3RP3_ODTOFF
Model_type   Input
C_comp 2.232pF   2.153pF   2.350pF
Vinh = 925.000mV
Vinl = 575.000mV
[Model Spec]
Vinh   925.000mV   888.000mV   963.000mV
Vinl   575.000mV   538.000mV   613.000mV
[Temperature Range]   25.000   125.000   -40.000
[Voltage Range]   1.500V   1.425V   1.575V
[GND Clamp Reference]   0.00V   0.00V   0.00V
[POWER Clamp Reference]   1.500V   1.425V   1.575V
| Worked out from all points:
|   GND clamp passes 1 mA (typ) near -0.40 V on its own axis
|   POWER clamp passes 1 mA (typ) near -0.41 V on its own axis
[GND Clamp]
-1.48V    -592.8mA   -479.1mA   -761.2mA
-1.098V   -217.8mA   -223.1mA   -219.7mA
-1.05V    -173.8mA   -192.1mA   -159.3mA
-1.002V   -131.7mA   -161.7mA   -105mA
-954.6mV  -92.68mA   -132.2mA   -61.41mA
-906.8mV  -58.93mA   -103.8mA   -35.09mA
-859.1mV  -33.75mA   -77.07mA   -25.6mA
-811.4mV  -19.88mA   -53.01mA   -21.59mA
-715.9mV  -11.39mA   -18.72mA   -15.38mA
-572.7mV  -5.408mA   -4.63mA    -7.309mA
-286.4mV  -67.53uA   -115uA     -52.79uA
2.959V    27.81nA    447.3nA    3.163nA
[Power Clamp]
-1.459V   573.5mA    476.8mA    715.7mA
-1.077V   209.6mA    224.3mA    208.4mA
-1.03V    167.1mA    193.7mA    154.3mA
-981.8mV  126.8mA    163.5mA    105.9mA
-934.1mV  89.99mA    134.1mA    67.88mA
-886.4mV  58.74mA    105.7mA    45.04mA
-838.6mV  36.05mA    79.08mA    34.56mA
-743.2mV  17.84mA    35.43mA    23.27mA
-647.7mV  10.73mA    12.81mA    14.31mA
-552.3mV  5.47mA     5.422mA    7.21mA
-313.6mV  99.22uA    231.1uA    112.6uA
2.98V     -43.92nA   -827.1nA   -4.178nA
